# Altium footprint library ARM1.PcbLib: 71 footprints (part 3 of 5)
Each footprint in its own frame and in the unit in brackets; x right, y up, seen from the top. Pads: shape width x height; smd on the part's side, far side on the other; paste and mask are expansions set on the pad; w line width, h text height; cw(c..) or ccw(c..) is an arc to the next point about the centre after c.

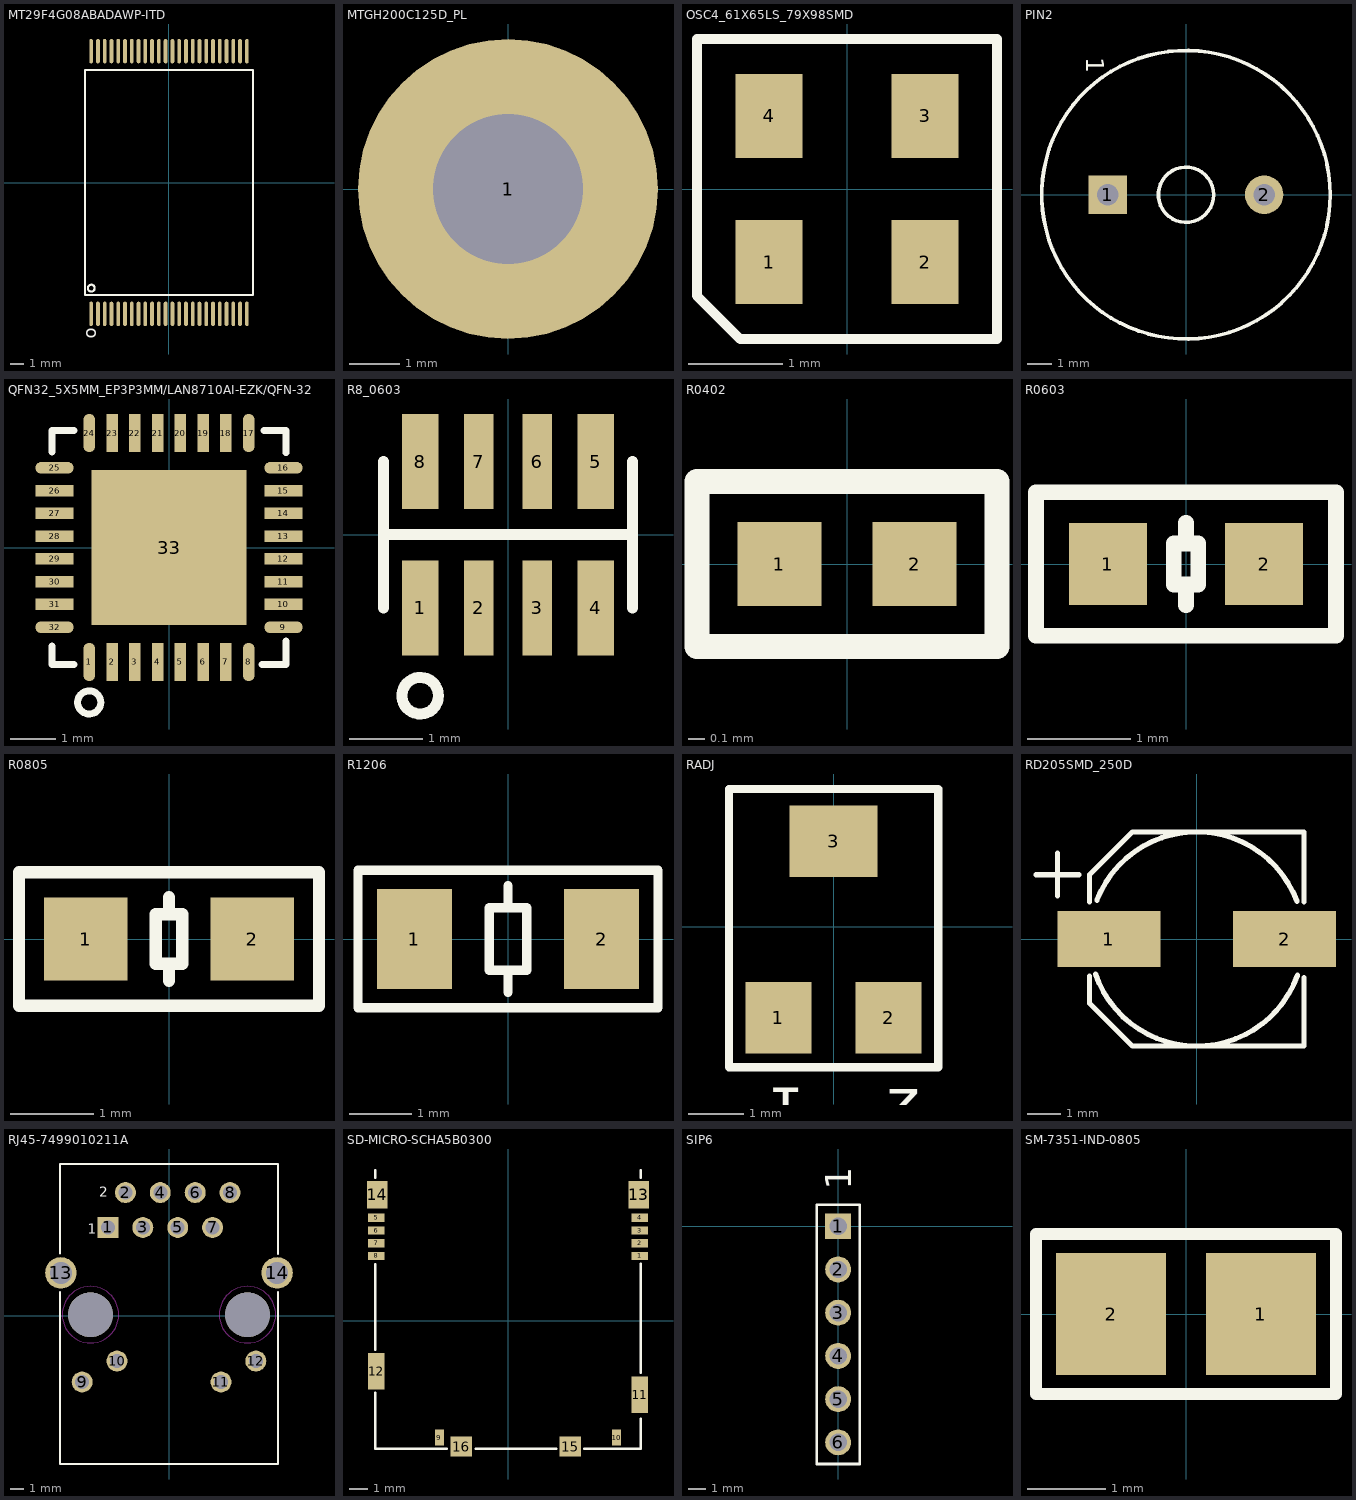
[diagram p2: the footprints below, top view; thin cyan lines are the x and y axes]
## MT29F4G08ABADAWP-ITD [mm]
pads (48):
  oval 0.28x1.8 smd: 1(-5.75,-9.7) 2(-5.25,-9.7) 3(-4.75,-9.7) 4(-4.25,-9.7) 5(-3.75,-9.7) 6(-3.25,-9.7) 7(-2.75,-9.7) 8(-2.25,-9.7) 9(-1.75,-9.7) 10(-1.25,-9.7) 11(-0.75,-9.7) 12(-0.25,-9.7) 13(0.25,-9.7) 14(0.75,-9.7) 15(1.25,-9.7) 16(1.75,-9.7) 17(2.25,-9.7) 18(2.75,-9.7) 19(3.25,-9.7) 20(3.75,-9.7) 21(4.25,-9.7) 22(4.75,-9.7) 23(5.25,-9.7) 24(5.75,-9.7) 25(5.75,9.7) 26(5.25,9.7) 27(4.75,9.7) 28(4.25,9.7) 29(3.75,9.7) 30(3.25,9.7) 31(2.75,9.7) 32(2.25,9.7) 33(1.75,9.7) 34(1.25,9.7) 35(0.75,9.7) 36(0.25,9.7) 37(-0.25,9.7) 38(-0.75,9.7) 39(-1.25,9.7) 40(-1.75,9.7) 41(-2.25,9.7) 42(-2.75,9.7) 43(-3.25,9.7) 44(-3.75,9.7) 45(-4.25,9.7) 46(-4.75,9.7) 47(-5.25,9.7) 48(-5.75,9.7)
Top Overlay:
  circle w0.152: c-5.74,-7.798 r0.254
  lines w0.15: -6.2,-8.3 -6.2,8.3 6.2,8.3 6.2,-8.3 -6.2,-8.3
  text "o" at -5.359,-11.557 h0.98

## MTGH200C125D_PL [mm] "MTGH200C125D_PL"
pads (1):
  round 6 hole 3 mask+0.051: 1(0,0)

## OSC4_61X65LS_79X98SMD [mil] "OSC4_61X65LS_79X98SMD"
pads (4):
  rect 28x35 smd mask+2: 1(-32.5,-30.5) 2(32.5,-30.5) 3(32.5,30.5) 4(-32.5,30.5)
Top Overlay:
  lines w4: -62.5,-44.5 -62.5,62.5 62.5,62.5 62.5,-62.5 -44.5,-62.5 -62.5,-44.5

## PIN2 [mm]
height 8.5
pads (2):
  rect 1.6x1.6 hole 0.9: 1(-3.25,0)
  round 1.6 hole 0.9: 2(3.25,0)
Top Overlay:
  circle w0.152: c0,0 r6
  circle w0.152: c0,0 r1.15
  text "1" at -4.14,5.715 h0.76

## QFN32_5X5MM_EP3P3MM/LAN8710AI-EZK/QFN-32 [mil]
height 39.37
pads (33):
  oval 10x33 smd mask+2: 1(-68.95,-99) 8(68.95,-99) 17(68.95,99) 24(-68.95,99)
  rect 10x33 smd mask+2: 2(-49.25,-99) 3(-29.55,-99) 4(-9.85,-99) 5(9.85,-99) 6(29.55,-99) 7(49.25,-99) 18(49.25,99) 19(29.55,99) 20(9.85,99) 21(-9.85,99) 22(-29.55,99) 23(-49.25,99)
  oval 33x10 smd mask+2: 9(99,-68.95) 16(99,68.95) 25(-99,68.95) 32(-99,-68.95)
  rect 33x10 smd mask+2: 10(99,-49.25) 11(99,-29.55) 12(99,-9.85) 13(99,9.85) 14(99,29.55) 15(99,49.25) 26(-99,49.25) 27(-99,29.55) 28(-99,9.85) 29(-99,-9.85) 30(-99,-29.55) 31(-99,-49.25)
  rect 134x134 smd mask+2: 33(0,0)
Top Overlay:
  circle w6: c-69,-134 r10
  lines w6: -101.29,-85 -101.29,-101.29 -82,-101.29 ; -101.29,82.5 -101.29,101.29 -82,101.29 ; 80.5,-101.29 101.29,-101.29 101.29,-81 ; 82,101.29 101.29,101.29 101.29,82

## R8_0603 [mm]
pads (8):
  rect 0.5x1.3 smd: 1(-1.2,-1) 4(1.2,-1) 5(1.2,1) 8(-1.2,1)
  rect 0.4x1.3 smd: 2(-0.4,-1) 3(0.4,-1) 6(0.4,1) 7(-0.4,1)
Top Overlay:
  circle w0.15: c-1.2,-2.2 r0.25
  lines w0.15: -1.7,-1 -1.7,1 ; -1.7,0 1.7,0 ; 1.7,-1 1.7,1

## R0402 [mm]
height 0.4
pads (2):
  rect 0.51x0.51 smd: 1(-0.41,0) 2(0.41,0)
Top Overlay:
  lines w0.152: -0.91,-0.5 -0.91,0.5 0.91,0.5 0.91,-0.5 -0.91,-0.5

## R0603 [mm]
height 0.6
pads (2):
  rect 0.76x0.8 smd: 1(-0.76,0) 2(0.76,0)
Top Overlay:
  lines w0.152: 0,-0.4 0,-0.2 ; 0,0.2 0,0.4 ; -1.46,-0.7 1.46,-0.7 1.46,0.7 -1.46,0.7 -1.46,-0.7 ; -0.12,-0.2 -0.12,0.2 0.12,0.2 0.12,-0.2 -0.12,-0.2

## R0805 [mm]
height 0.65
pads (2):
  rect 1x1 smd: 1(-1,0) 2(1,0)
Top Overlay:
  lines w0.15: 0,-0.5 0,-0.3 ; 0,0.3 0,0.5 ; -1.8,-0.8 1.8,-0.8 1.8,0.8 -1.8,0.8 -1.8,-0.8 ; -0.16,-0.3 0.16,-0.3 0.16,0.3 -0.16,0.3 -0.16,-0.3

## R1206 [mm]
height 0.71
pads (2):
  rect 1.2x1.6 smd: 1(-1.5,0) 2(1.5,0)
Top Overlay:
  lines w0.15: 0,-0.85 0,-0.5 ; 0,0.5 0,0.85 ; -2.4,-1.1 2.4,-1.1 2.4,1.1 -2.4,1.1 -2.4,-1.1 ; -0.3,-0.5 -0.3,0.5 0.3,0.5 0.3,-0.5 -0.3,-0.5

## RADJ [mm] "RADJ"
pads (3):
  rect 1.2x1.3 smd: 1(-1,-1.65) 2(1,-1.65)
  rect 1.6x1.3 smd: 3(0,1.55)
Top Overlay:
  lines w0.15: -1.9,-2.55 -1.9,2.5 1.9,2.5 1.9,-2.55 -1.9,-2.55
  text "2" at 1.6,-2.946 h0.79
  text "1" at -0.508,-2.921 h0.79

## RD205SMD_250D [mil] "RD205SMD_250D"
pads (2):
  rect 120x65 smd mask+2: 1(-102.5,0) 2(102.5,0)
Top Overlay:
  lines w6: -187.5,75 -137.5,75 ; -162.5,50 -162.5,100 ; -125,-43 -125,-75 -75,-125 125,-125 125,-45 ; -125,43 -125,75 -75,125 125,125 125,43 ; -118.2,-40.66 ccw(c0,0) 117.61,-42.34 ; -116.52,45.25 cw(c0,0) 117,44

## RJ45-7499010211A [mil] "RJ45-7499010211A"
pads (16):
  rect 60x60 hole 40 mask+2: 1(-175,252.5)
  round 60 hole 40 mask+2: 2(-125,352.5) 3(-75,252.5) 4(-25,352.5) 5(25,252.5) 6(75,352.5) 7(125,252.5) 8(175,352.5) 9(-249,-190.5) 10(-149,-130.5) 11(149,-190.5) 12(249,-130.5)
  round 90 hole 63 mask+2: 13(-310,122.5) 14(310,122.5)
  round 128 hole 128 unplated: " "(-225,2.5)
  round 128 hole 128 unplated mask+2: " "(225,2.5)
Top Overlay:
  lines w6: -313,67 -313,-425.5 313,-425.5 313,67 ; -313,178 -313,434.5 313,434.5 313,177
  text "1" at -233,235 h28
  text "2" at -200,340 h28
Keep-Out Layer:
  circle w1: c-225,2.5 r81
  circle w1: c225,2.5 r81

## SD-MICRO-SCHA5B0300 [mil] "SD-MICRO-SCHA5B0300"
pads (16):
  rect 36x18 smd mask+2: 1(285.72,140.22) 2(285.72,167.78) 3(285.72,195.34) 4(285.72,222.9) 5(-285.72,222.9) 6(-285.72,195.34) 7(-285.72,167.78) 8(-285.72,140.22)
  rect 20x35 smd mask+2: 9(-148.62,-253.06) 10(235.24,-253.06)
  rect 35x79 smd mask+2: 11(285.43,-160.38) 12(-285.43,-109.19)
  rect 44x60 smd mask+2: 13(283.32,272.69) 14(-283.32,272.69)
  rect 47x43 smd mask+2: 15(134.84,-272.69) 16(-101.37,-272.69)
Top Overlay:
  lines w6: -287.5,-156.78 -287.5,-277.29 -132.5,-277.29 ; -287.5,-62.28 -287.5,122.27 ; -287.5,309.71 -287.5,325.21 ; -70,-277.29 104.5,-277.29 ; 165.5,-277.29 287.5,-277.29 287.5,-213 ; 287.5,-112.78 287.5,123.22 ; 287.5,309.71 287.5,325.21

## SIP6 [mil] "SIP6"
pads (6):
  rect 60x60 hole 40 mask+2: 1(0,0)
  round 60 hole 40 mask+2: 2(0,-100) 3(0,-200) 4(0,-300) 5(0,-400) 6(0,-500)
Top Overlay:
  lines w6: -50,-550 -50,50 50,50 50,-550 -50,-550
  text "1" at 30.82,84 h60

## SM-7351-IND-0805 [mil] "SM-7351-IND-0805"
pads (2):
  rect 55x61 smd mask+2: 1(37.4,0) 2(-37.4,0)
Top Overlay:
  lines w6: -75,-40 -75,40 75,40 75,-40 -75,-40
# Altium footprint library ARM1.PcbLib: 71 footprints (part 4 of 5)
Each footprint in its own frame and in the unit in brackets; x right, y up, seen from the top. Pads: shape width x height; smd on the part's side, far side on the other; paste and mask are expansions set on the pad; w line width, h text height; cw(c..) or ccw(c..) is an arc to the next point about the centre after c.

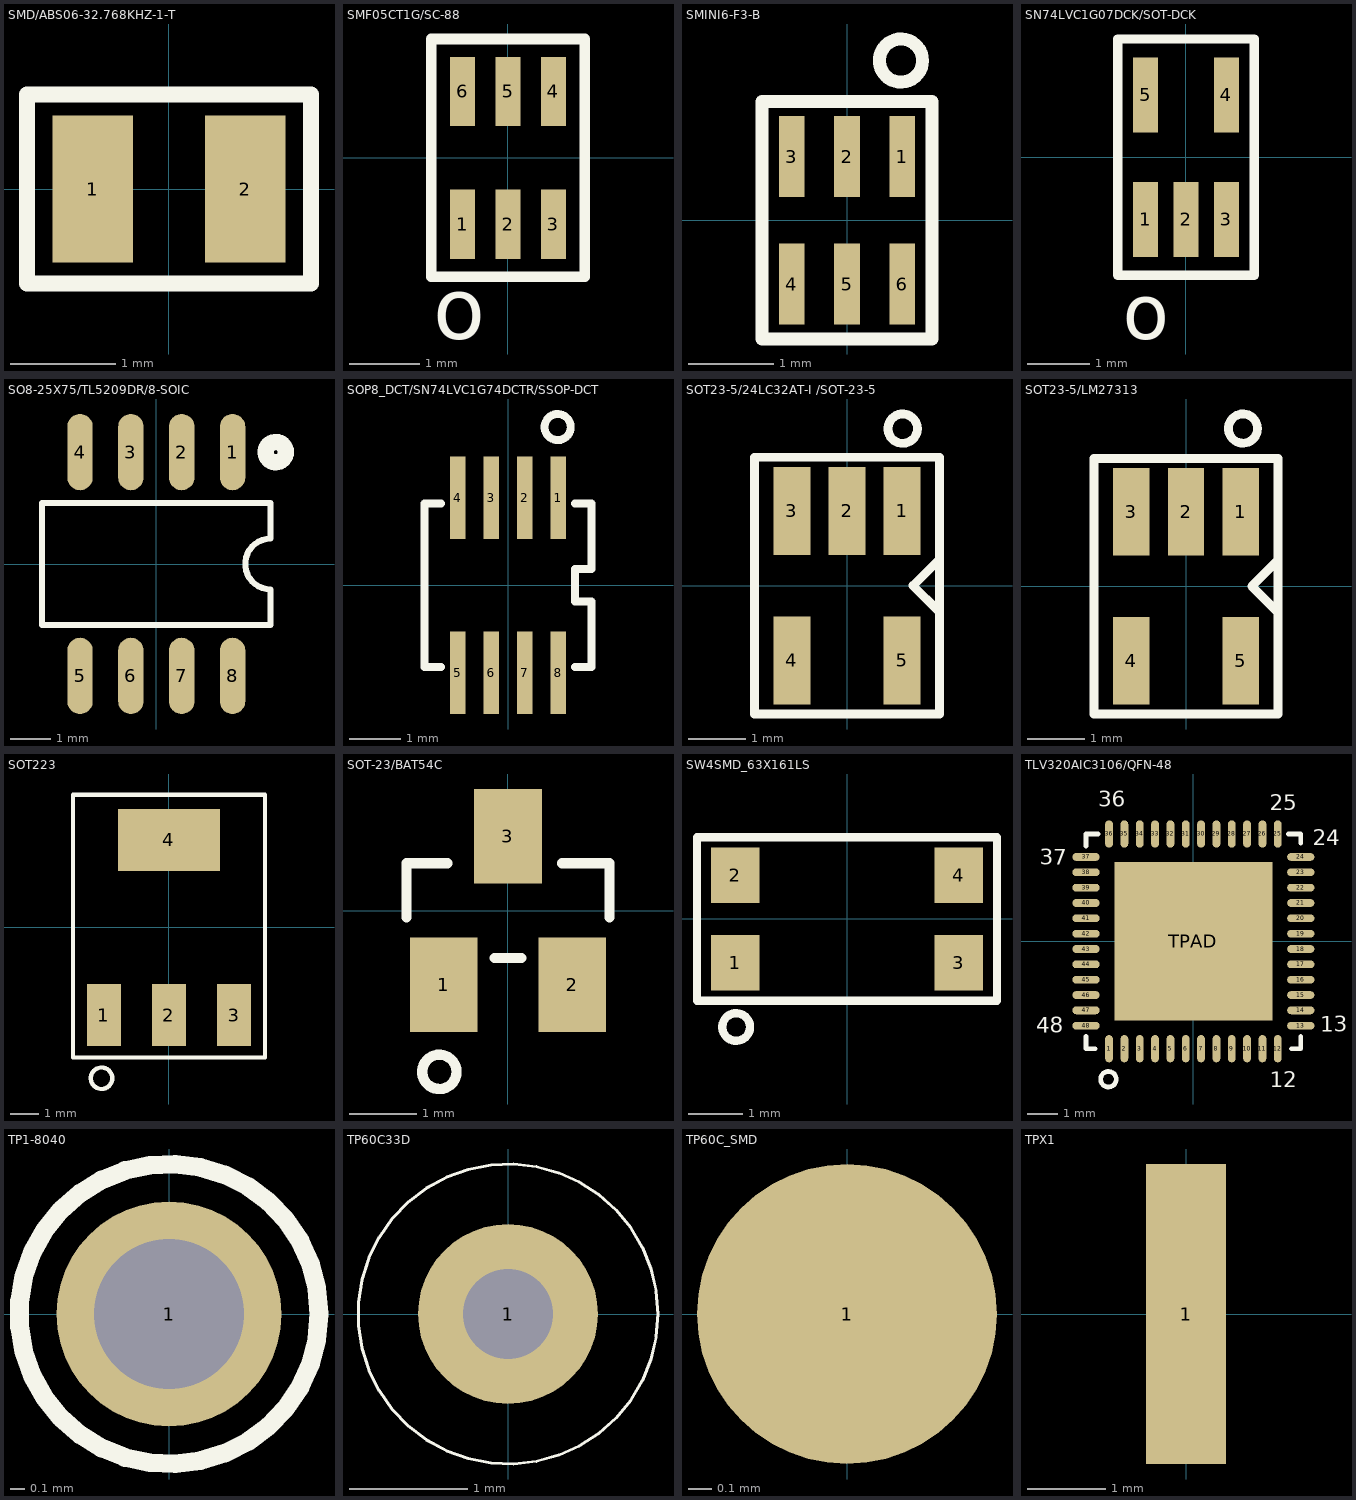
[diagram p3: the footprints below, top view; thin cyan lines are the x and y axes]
## SMD/ABS06-32.768KHZ-1-T [mm]
height 0.6
pads (2):
  rect 0.762x1.4 smd mask+0.051: 1(-0.725,0) 2(0.725,0)
Top Overlay:
  lines w0.152: -1.35,-0.9 1.35,-0.9 1.35,0.9 -1.35,0.9 -1.35,-0.9

## SMF05CT1G/SC-88 [mil]
pads (6):
  rect 14x39 smd: 1(-25.59,-37.4) 2(0,-37.4) 3(25.59,-37.4) 4(25.59,37.4) 5(0,37.4) 6(-25.59,37.4)
Top Overlay:
  lines w6: -43.31,-66.93 -43.31,66.93 43.31,66.93 43.31,-66.93 -43.31,-66.93
  text "o" at -42,-102 h35

## SMINI6-F3-B [mil] "SMINI6-F3-B"
pads (6):
  rect 12x37.4 smd mask+2: 1(25.59,29.53) 2(0,29.53) 3(-25.59,29.53) 4(-25.59,-29.53) 5(0,-29.53) 6(25.59,-29.53)
Top Overlay:
  circle w6: c25,74 r10
  lines w6: -39.37,-55 -39.37,55 39.37,55 39.37,-55 -39.37,-55

## SN74LVC1G07DCK/SOT-DCK [mm]
pads (5):
  rect 0.4x1.2 smd: 1(-0.65,-1) 2(0,-1) 3(0.65,-1) 4(0.65,1) 5(-0.65,1)
Top Overlay:
  lines w0.152: -1.1,-1.9 1.1,-1.9 1.1,1.9 -1.1,1.9 -1.1,-1.9
  text "o" at -1.016,-2.921 h0.89

## SO8-25X75/TL5209DR/8-SOIC [mil]
pads (8):
  oval 25x75 smd mask+2: 1(75,110) 2(25,110) 3(-25,110) 4(-75,110) 5(-75,-110) 6(-25,-110) 7(25,-110) 8(75,-110)
Top Overlay:
  circle w6: c117.5,110 r15
  circle w6: c117.5,110 r10
  circle w6: c117.5,110 r5
  lines w6: -112.5,-60 112.5,-60 112.5,-25 cw(c112.5,0) 112.5,25 112.5,60 -112.5,60 -112.5,-60

## SOP8_DCT/SN74LVC1G74DCTR/SSOP-DCT [mil]
pads (8):
  rect 12x63 smd mask+2: 1(38.4,67) 2(12.8,67) 3(-12.8,67) 4(-38.4,67) 5(-38.4,-67) 6(-12.8,-67) 7(12.8,-67) 8(38.4,-67)
Top Overlay:
  circle w6: c38,121 r10
  lines w6: -51.2,-62.5 -64,-62.5 -64,62.5 -51.2,62.5 ; 51.2,-62.5 64,-62.5 64,-12.5 51.2,-12.5 51.2,12.5 64,12.5 64,62.5 51.2,62.5

## SOT23-5/24LC32AT-I /SOT-23-5 [mil]
height 57.09
pads (5):
  rect 25x60 smd mask+2: 1(37.5,51) 2(0,51) 3(-37.5,51) 4(-37.5,-51) 5(37.5,-51)
Top Overlay:
  circle w6: c38,107 r10
  lines w6: 62.5,-17.5 45,0 62.5,17.5 ; -62.99,-87.5 -62.99,87.5 62.99,87.5 62.99,-87.5 -62.99,-87.5

## SOT23-5/LM27313 [mil]
height 48.03
pads (5):
  rect 25x60 smd mask+2: 1(37.5,51) 2(0,51) 3(-37.5,51) 4(-37.5,-51) 5(37.5,-51)
Top Overlay:
  circle w6: c39,108 r10
  lines w6: 62.5,-17.5 45,0 62.5,17.5 ; -62.99,-87.5 -62.99,87.5 62.99,87.5 62.99,-87.5 -62.99,-87.5

## SOT223 [mm]
height 1.8
pads (4):
  rect 1.2x2.2 smd: 1(-2.3,-3.1) 2(0,-3.1) 3(2.3,-3.1)
  rect 3.6x2.2 smd: 4(0,3.1)
Top Overlay:
  circle w0.152: c-2.388,-5.334 r0.381
  lines w0.15: -3.4,-4.6 -3.4,4.7 3.4,4.7 3.4,-4.6 -3.4,-4.6

## SOT-23/BAT54C [mm]
pads (3):
  rect 1x1.4 smd: 1(-0.95,-1.1) 2(0.95,-1.1) 3(0,1.1)
Top Overlay:
  circle w0.152: c-1.016,-2.388 r0.254
  lines w0.15: -1.5,-0.1 -1.5,0.7 -0.9,0.7 ; -0.2,-0.7 0.2,-0.7 ; 0.8,0.7 1.5,0.7 1.5,-0.1

## SW4SMD_63X161LS [mil] "SW4SMD_63X161LS"
pads (4):
  rect 35x40 smd mask+2: 1(-80.71,-31.5) 2(-80.71,31.5) 3(80.71,-31.5) 4(80.71,31.5)
Top Overlay:
  circle w6: c-80,-78 r10
  lines w6: -108.27,-59.06 108.27,-59.06 108.27,59.06 -108.27,59.06 -108.27,-59.06

## TLV320AIC3106/QFN-48 [mil]
height 39.37
pads (49):
  oval 10x35 smd: 1(-108.27,-137.8) 2(-88.58,-137.8) 3(-68.9,-137.8) 4(-49.21,-137.8) 5(-29.53,-137.8) 6(-9.84,-137.8) 7(9.84,-137.8) 8(29.53,-137.8) 9(49.21,-137.8) 10(68.9,-137.8) 11(88.58,-137.8) 12(108.27,-137.8) 25(108.27,137.8) 26(88.58,137.8) 27(68.9,137.8) 28(49.21,137.8) 29(29.53,137.8) 30(9.84,137.8) 31(-9.84,137.8) 32(-29.53,137.8) 33(-49.21,137.8) 34(-68.9,137.8) 35(-88.58,137.8) 36(-108.27,137.8)
  oval 35x10 smd: 13(137.8,-108.27) 14(137.8,-88.58) 15(137.8,-68.9) 16(137.8,-49.21) 17(137.8,-29.53) 18(137.8,-9.84) 19(137.8,9.84) 20(137.8,29.53) 21(137.8,49.21) 22(137.8,68.9) 23(137.8,88.58) 24(137.8,108.27) 37(-137.8,108.27) 38(-137.8,88.58) 39(-137.8,68.9) 40(-137.8,49.21) 41(-137.8,29.53) 42(-137.8,9.84) 43(-137.8,-9.84) 44(-137.8,-29.53) 45(-137.8,-49.21) 46(-137.8,-68.9) 47(-137.8,-88.58) 48(-137.8,-108.27)
  rect 203x203 smd: TPAD(0,0)
Top Overlay:
  circle w6: c-109,-177 r10
  lines w6: -137.8,-122.05 -137.8,-137.8 -125.98,-137.8 ; -137.8,122.05 -137.8,137.8 -122.05,137.8 ; 122.05,137.8 137.8,137.8 137.8,125.98 ; 125.98,-137.8 137.8,-137.8 137.8,-122.05
  text "48" at -202,-117 h20
  text "37" at -197,98 h20
  text "36" at -122,173 h20
  text "25" at 98,168 h20
  text "24" at 153,123 h20
  text "13" at 163,-116 h20
  text "12" at 98,-187 h20

## TP1-8040 [mil] "TP1-8040"
pads (1):
  round 60 hole 40 mask+2: 1(0,0)
Top Overlay:
  circle w5: c0,0 r40

## TP60C33D [mil] "TP60C33D"
pads (1):
  round 60 hole 30 mask+2: 1(0,0)
Top Overlay:
  circle w1: c0,0 r50

## TP60C_SMD [mil] "TP60C_SMD"
pads (1):
  round 50 smd mask+2: 1(0,0)

## TPX1 [mil]
pads (1):
  rect 40x150 smd: 1(0,0)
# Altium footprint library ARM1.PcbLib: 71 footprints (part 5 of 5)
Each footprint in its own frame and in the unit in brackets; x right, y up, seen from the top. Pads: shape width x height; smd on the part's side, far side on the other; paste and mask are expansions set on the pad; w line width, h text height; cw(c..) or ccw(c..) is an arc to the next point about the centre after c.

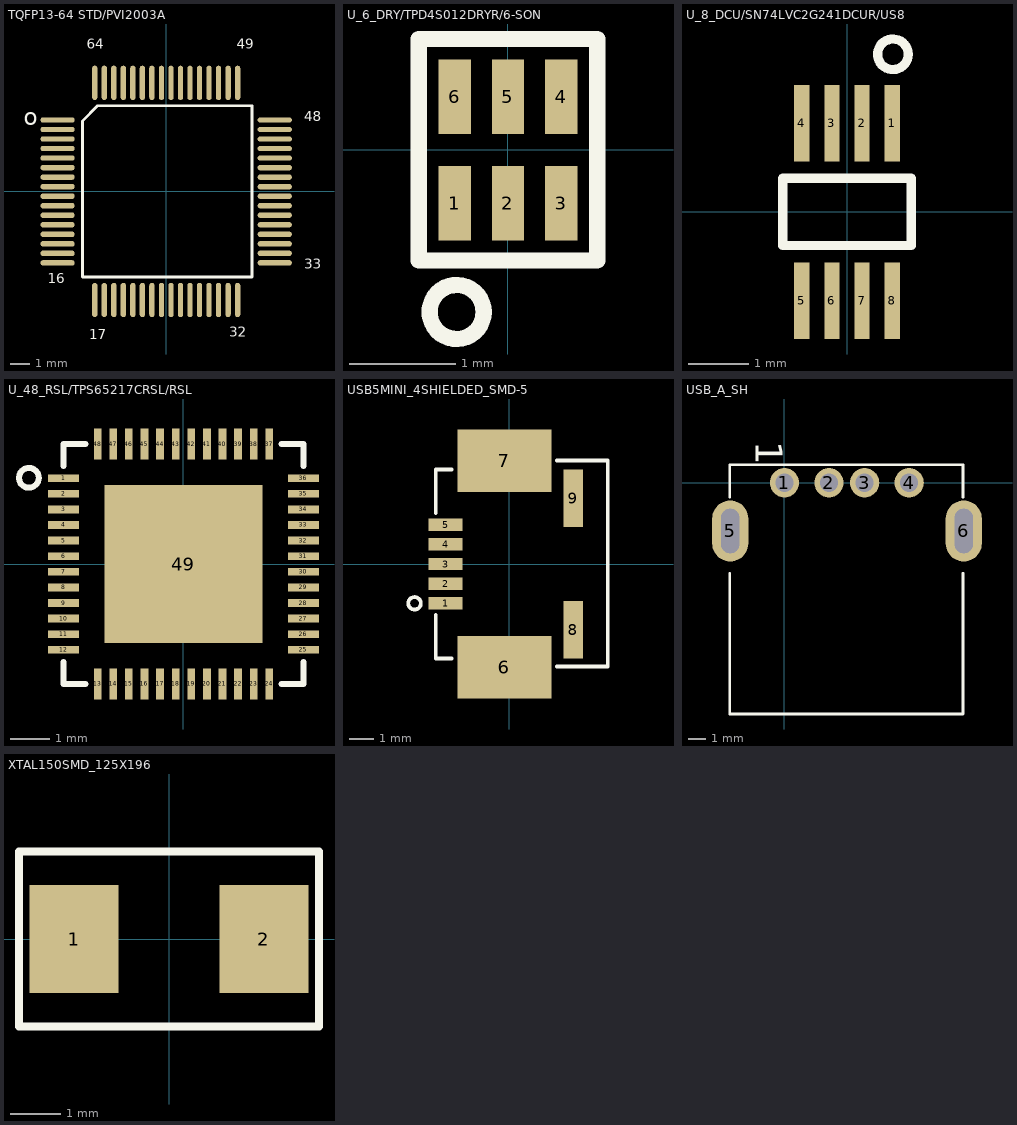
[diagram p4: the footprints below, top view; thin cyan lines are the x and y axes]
## TQFP13-64 STD/PVI2003A [mm]
height 1.2
pads (64):
  oval 1.8x0.28 smd: 1(-5.7,3.75) 2(-5.7,3.25) 3(-5.7,2.75) 4(-5.7,2.25) 5(-5.7,1.75) 6(-5.7,1.25) 7(-5.7,0.75) 8(-5.7,0.25) 9(-5.7,-0.25) 10(-5.7,-0.75) 11(-5.7,-1.25) 12(-5.7,-1.75) 13(-5.7,-2.25) 14(-5.7,-2.75) 15(-5.7,-3.25) 16(-5.7,-3.75) 33(5.7,-3.75) 34(5.7,-3.25) 35(5.7,-2.75) 36(5.7,-2.25) 37(5.7,-1.75) 38(5.7,-1.25) 39(5.7,-0.75) 40(5.7,-0.25) 41(5.7,0.25) 42(5.7,0.75) 43(5.7,1.25) 44(5.7,1.75) 45(5.7,2.25) 46(5.7,2.75) 47(5.7,3.25) 48(5.7,3.75)
  oval 0.28x1.8 smd: 17(-3.75,-5.7) 18(-3.25,-5.7) 19(-2.75,-5.7) 20(-2.25,-5.7) 21(-1.75,-5.7) 22(-1.25,-5.7) 23(-0.75,-5.7) 24(-0.25,-5.7) 25(0.25,-5.7) 26(0.75,-5.7) 27(1.25,-5.7) 28(1.75,-5.7) 29(2.25,-5.7) 30(2.75,-5.7) 31(3.25,-5.7) 32(3.75,-5.7) 49(3.75,5.7) 50(3.25,5.7) 51(2.75,5.7) 52(2.25,5.7) 53(1.75,5.7) 54(1.25,5.7) 55(0.75,5.7) 56(0.25,5.7) 57(-0.25,5.7) 58(-0.75,5.7) 59(-1.25,5.7) 60(-1.75,5.7) 61(-2.25,5.7) 62(-2.75,5.7) 63(-3.25,5.7) 64(-3.75,5.7)
Top Overlay:
  lines w0.15: -4.4,-4.5 4.5,-4.5 4.5,4.5 -3.6,4.5 -4.4,3.7 -4.4,-4.5
  text "64" at -4.175,7.493 h0.51
  text "49" at 3.699,7.493 h0.51
  text "48" at 7.255,3.683 h0.51
  text "33" at 7.255,-4.064 h0.51
  text "32" at 3.318,-7.62 h0.51
  text "17" at -4.048,-7.747 h0.51
  text "16" at -6.207,-4.826 h0.51
  text "o" at -7.468,3.48 h0.89

## U_6_DRY/TPD4S012DRYR/6-SON [mm]
pads (6):
  rect 0.305x0.7 smd mask+0.051: 1(-0.5,-0.5) 2(0,-0.5) 3(0.5,-0.5) 4(0.5,0.5) 5(0,0.5) 6(-0.5,0.5)
Top Overlay:
  circle w0.152: c-0.483,-1.524 r0.254
  lines w0.152: -0.838,-1.041 0.838,-1.041 0.838,1.041 -0.838,1.041 -0.838,-1.041

## U_8_DCU/SN74LVC2G241DCUR/US8 [mil]
height 35.43
pads (8):
  rect 10x50 smd mask+2: 1(29.53,58) 2(9.84,58) 3(-9.84,58) 4(-29.53,58) 5(-29.53,-58) 6(-9.84,-58) 7(9.84,-58) 8(29.53,-58)
Top Overlay:
  circle w6: c30,103 r10
  lines w6: -42,-22 42,-22 42,22 -42,22 -42,-22

## U_48_RSL/TPS65217CRSL/RSL [mil]
height 39.37
pads (49):
  rect 31.5x7.87 smd mask+2: 1(-121.06,86.61) 2(-121.06,70.87) 3(-121.06,55.12) 4(-121.06,39.37) 5(-121.06,23.62) 6(-121.06,7.87) 7(-121.06,-7.87) 8(-121.06,-23.62) 9(-121.06,-39.37) 10(-121.06,-55.12) 11(-121.06,-70.87) 12(-121.06,-86.61) 25(121.06,-86.61) 26(121.06,-70.87) 27(121.06,-55.12) 28(121.06,-39.37) 29(121.06,-23.62) 30(121.06,-7.87) 31(121.06,7.87) 32(121.06,23.62) 33(121.06,39.37) 34(121.06,55.12) 35(121.06,70.87) 36(121.06,86.61)
  rect 7.87x31.5 smd mask+2: 13(-86.61,-121.06) 14(-70.87,-121.06) 15(-55.12,-121.06) 16(-39.37,-121.06) 17(-23.62,-121.06) 18(-7.87,-121.06) 19(7.87,-121.06) 20(23.62,-121.06) 21(39.37,-121.06) 22(55.12,-121.06) 23(70.87,-121.06) 24(86.61,-121.06) 37(86.61,121.06) 38(70.87,121.06) 39(55.12,121.06) 40(39.37,121.06) 41(23.62,121.06) 42(7.87,121.06) 43(-7.87,121.06) 44(-23.62,121.06) 45(-39.37,121.06) 46(-55.12,121.06) 47(-70.87,121.06) 48(-86.61,121.06)
  rect 159.45x159.45 smd mask+2: 49(0,0)
Top Overlay:
  circle w6: c-156,87 r10
  lines w6: -121.06,-98.94 -121.06,-121.06 -98.94,-121.06 ; -121.06,98.94 -121.06,121.06 -98.94,121.06 ; 98.94,-121.06 121.06,-121.06 121.06,-98.94 ; 98.94,121.06 121.06,121.06 121.06,98.94

## USB5MINI_4SHIELDED_SMD-5 [mil] "USB5MINI_4SHIELDED_SMD-5"
pads (9):
  rect 55.12x19.69 smd mask+2: 1(-102.36,-62.99) 2(-102.36,-31.5) 3(-102.36,0) 4(-102.36,31.5) 5(-102.36,62.99)
  rect 150x100 smd mask+2: 6(-7.87,-165.35) 7(-7.87,165.35)
  rect 31.5x92.52 smd mask+2: 8(102.36,-105.31) 9(102.36,105.31)
Top Overlay:
  circle w6: c-152,-63 r10
  lines w6: -118.11,-81.14 -118.11,-151.57 -92.68,-151.57 ; -118.11,81.14 -118.11,151.57 -92.68,151.57 ; 75.75,-164.22 157.48,-164.22 157.48,165.78 75.75,165.78

## USB_A_SH [mil]
pads (6):
  round 65 hole 40 mask+2: 1(0,0) 2(98.4,0) 3(177.2,0) 4(275.6,0)
  oval 80x135 hole 40 slot 98.43 at 90 deg mask+2: 5(-120,-106.7) 6(396.5,-106.7)
Top Overlay:
  lines w6: -120.9,-200 -120.9,-511.4 394.9,-511.4 394.9,-200 ; -120.9,-32 -120.9,39.8 394.9,39.8 394.9,-32
  text "1" at -64,92 h60

## XTAL150SMD_125X196 [mil] "XTAL150SMD_125X196"
pads (2):
  rect 70x85 smd mask+2: 1(-74.8,0) 2(74.8,0)
Top Overlay:
  lines w6: -118.11,-68.9 118.11,-68.9 118.11,68.9 -118.11,68.9 -118.11,-68.9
